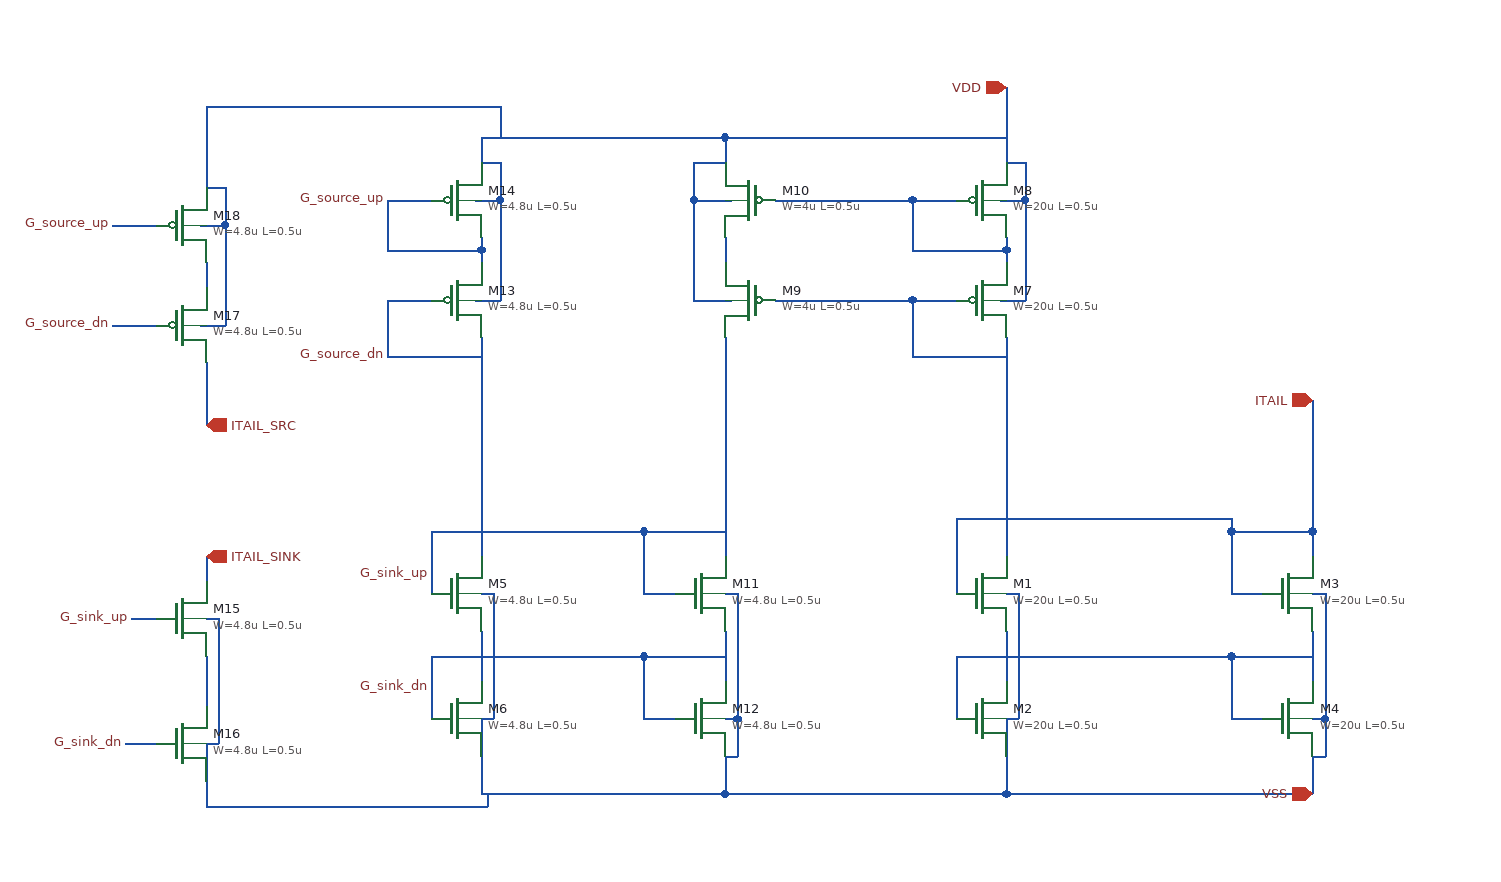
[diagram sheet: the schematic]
v {xschem version=3.4.3 file_version=1.2
}
G {}
K {}
V {}
S {}
E {}
N 575 -225 585 -225 {
lab=VSS}
N 585 -225 585 -125 {
lab=VSS}
N 575 -125 585 -125 {
lab=VSS}
N 575 -190 575 -160 {
lab=#net1}
N 575 -195 575 -190 {
lab=#net1}
N 575 -160 575 -155 {
lab=#net1}
N 575 -125 575 -70 {
lab=VSS}
N 575 -265 575 -255 {
lab=#net2}
N 575 -70 575 -65 {
lab=VSS}
N 575 -430 575 -265 {
lab=#net2}
N 500 -540 535 -540 {
lab=#net3}
N 500 -540 500 -500 {
lab=#net3}
N 500 -500 575 -500 {
lab=#net3}
N 575 -510 575 -500 {
lab=#net3}
N 575 -500 575 -490 {
lab=#net3}
N 570 -460 590 -460 {
lab=VDD}
N 590 -540 590 -460 {
lab=VDD}
N 570 -540 590 -540 {
lab=VDD}
N 590 -570 590 -540 {
lab=VDD}
N 575 -570 590 -570 {
lab=VDD}
N 575 -630 575 -570 {
lab=VDD}
N 500 -460 535 -460 {
lab=#net2}
N 500 -460 500 -415 {
lab=#net2}
N 500 -415 575 -415 {
lab=#net2}
N 390 -540 500 -540 {
lab=#net3}
N 390 -460 500 -460 {
lab=#net2}
N 350 -510 350 -490 {
lab=#net4}
N 350 -590 350 -570 {
lab=VDD}
N 350 -590 575 -590 {
lab=VDD}
N 350 -430 350 -355 {
lab=G_sink_up}
N 325 -460 355 -460 {
lab=VDD}
N 325 -540 325 -460 {
lab=VDD}
N 325 -540 355 -540 {
lab=VDD}
N 325 -540 355 -540 {
lab=VDD}
N 325 -570 325 -540 {
lab=VDD}
N 325 -570 350 -570 {
lab=VDD}
N 350 -355 350 -255 {
lab=G_sink_up}
N 350 -195 350 -155 {
lab=#net5}
N 350 -225 360 -225 {
lab=VSS}
N 360 -225 360 -125 {
lab=VSS}
N 350 -125 360 -125 {
lab=VSS}
N 350 -125 360 -125 {
lab=VSS}
N 360 -125 360 -95 {
lab=VSS}
N 350 -95 360 -95 {
lab=VSS}
N 350 -95 350 -65 {
lab=VSS}
N 350 -65 575 -65 {
lab=VSS}
N 285 -225 310 -225 {
lab=G_sink_up}
N 285 -275 285 -225 {
lab=G_sink_up}
N 285 -175 350 -175 {
lab=#net5}
N 285 -175 285 -125 {
lab=#net5}
N 285 -125 310 -125 {
lab=#net5}
N 285 -275 350 -275 {
lab=G_sink_up}
N 535 -285 535 -225 {
lab=ITAIL}
N 535 -285 755 -285 {
lab=ITAIL}
N 535 -175 535 -125 {
lab=#net6}
N 535 -175 750 -175 {
lab=#net6}
N 820 -195 820 -155 {
lab=#net6}
N 820 -225 830 -225 {
lab=VSS}
N 830 -225 830 -125 {
lab=VSS}
N 820 -125 830 -125 {
lab=VSS}
N 820 -125 830 -125 {
lab=VSS}
N 830 -125 830 -95 {
lab=VSS}
N 820 -95 830 -95 {
lab=VSS}
N 820 -95 820 -65 {
lab=VSS}
N 755 -225 780 -225 {
lab=ITAIL}
N 755 -275 755 -225 {
lab=ITAIL}
N 755 -175 820 -175 {
lab=#net6}
N 755 -175 755 -125 {
lab=#net6}
N 755 -125 780 -125 {
lab=#net6}
N 755 -275 820 -275 {
lab=ITAIL}
N 750 -175 755 -175 {
lab=#net6}
N 755 -285 755 -275 {
lab=ITAIL}
N 820 -275 820 -255 {
lab=ITAIL}
N 575 -65 820 -65 {
lab=VSS}
N 820 -380 820 -275 {
lab=ITAIL}
N 155 -225 165 -225 {
lab=VSS}
N 165 -225 165 -125 {
lab=VSS}
N 155 -125 165 -125 {
lab=VSS}
N 155 -190 155 -160 {
lab=#net7}
N 155 -195 155 -190 {
lab=#net7}
N 155 -160 155 -155 {
lab=#net7}
N 155 -265 155 -255 {
lab=G_source_dn}
N 155 -430 155 -265 {
lab=G_source_dn}
N 80 -540 115 -540 {
lab=G_source_up}
N 80 -540 80 -500 {
lab=G_source_up}
N 80 -500 155 -500 {
lab=G_source_up}
N 155 -510 155 -500 {
lab=G_source_up}
N 155 -500 155 -490 {
lab=G_source_up}
N 150 -460 170 -460 {
lab=VDD}
N 170 -540 170 -460 {
lab=VDD}
N 150 -540 170 -540 {
lab=VDD}
N 170 -570 170 -540 {
lab=VDD}
N 155 -570 170 -570 {
lab=VDD}
N 80 -460 115 -460 {
lab=G_source_dn}
N 80 -460 80 -415 {
lab=G_source_dn}
N 80 -415 155 -415 {
lab=G_source_dn}
N 115 -175 115 -125 {
lab=#net5}
N 155 -95 155 -65 {
lab=VSS}
N 155 -65 350 -65 {
lab=VSS}
N 155 -125 155 -95 {
lab=VSS}
N 155 -590 350 -590 {
lab=VDD}
N 155 -590 155 -570 {
lab=VDD}
N 115 -275 285 -275 {
lab=G_sink_up}
N 115 -275 115 -225 {
lab=G_sink_up}
N 115 -175 285 -175 {
lab=#net5}
N -65 -205 -55 -205 {
lab=VSS}
N -55 -205 -55 -105 {
lab=VSS}
N -65 -105 -55 -105 {
lab=VSS}
N -65 -170 -65 -140 {
lab=#net8}
N -65 -175 -65 -170 {
lab=#net8}
N -65 -140 -65 -135 {
lab=#net8}
N -65 -245 -65 -235 {
lab=ITAIL_SINK}
N -140 -520 -105 -520 {
lab=G_source_up}
N -65 -490 -65 -480 {
lab=#net9}
N -65 -480 -65 -470 {
lab=#net9}
N -70 -440 -50 -440 {
lab=VDD}
N -50 -520 -50 -440 {
lab=VDD}
N -70 -520 -50 -520 {
lab=VDD}
N -50 -550 -50 -520 {
lab=VDD}
N -65 -550 -50 -550 {
lab=VDD}
N -140 -440 -105 -440 {
lab=G_source_dn}
N -65 -105 -65 -75 {
lab=VSS}
N -65 -570 -65 -550 {
lab=VDD}
N -65 -255 -65 -245 {
lab=ITAIL_SINK}
N -130 -105 -105 -105 {
lab=G_sink_dn}
N -65 -615 -65 -570 {
lab=VDD}
N -65 -615 170 -615 {
lab=VDD}
N 170 -615 170 -590 {
lab=VDD}
N -65 -75 -65 -55 {
lab=VSS}
N -65 -55 160 -55 {
lab=VSS}
N 160 -65 160 -55 {
lab=VSS}
N -125 -205 -105 -205 {
lab=G_sink_up}
N -65 -410 -65 -360 {
lab=ITAIL_SRC}
C {symbols/nfet_03v3.sym} 555 -225 0 0 {name=M1
L=0.5u
W=20u
nf=1
m=1
ad="'int((nf+1)/2) * W/nf * 0.18u'"
pd="'2*int((nf+1)/2) * (W/nf + 0.18u)'"
as="'int((nf+2)/2) * W/nf * 0.18u'"
ps="'2*int((nf+2)/2) * (W/nf + 0.18u)'"
nrd="'0.18u / W'" nrs="'0.18u / W'"
sa=0 sb=0 sd=0
model=nfet_03v3
spiceprefix=X
}
C {symbols/nfet_03v3.sym} 555 -125 0 0 {name=M2
L=0.5u
W=20u
nf=1
m=1
ad="'int((nf+1)/2) * W/nf * 0.18u'"
pd="'2*int((nf+1)/2) * (W/nf + 0.18u)'"
as="'int((nf+2)/2) * W/nf * 0.18u'"
ps="'2*int((nf+2)/2) * (W/nf + 0.18u)'"
nrd="'0.18u / W'" nrs="'0.18u / W'"
sa=0 sb=0 sd=0
model=nfet_03v3
spiceprefix=X
}
C {symbols/pfet_03v3.sym} 555 -460 0 0 {name=M7
L=0.5u
W=20u
nf=1
m=1
ad="'int((nf+1)/2) * W/nf * 0.18u'"
pd="'2*int((nf+1)/2) * (W/nf + 0.18u)'"
as="'int((nf+2)/2) * W/nf * 0.18u'"
ps="'2*int((nf+2)/2) * (W/nf + 0.18u)'"
nrd="'0.18u / W'" nrs="'0.18u / W'"
sa=0 sb=0 sd=0
model=pfet_03v3
spiceprefix=X
}
C {symbols/pfet_03v3.sym} 555 -540 0 0 {name=M8
L=0.5u
W=20u
nf=1
m=1
ad="'int((nf+1)/2) * W/nf * 0.18u'"
pd="'2*int((nf+1)/2) * (W/nf + 0.18u)'"
as="'int((nf+2)/2) * W/nf * 0.18u'"
ps="'2*int((nf+2)/2) * (W/nf + 0.18u)'"
nrd="'0.18u / W'" nrs="'0.18u / W'"
sa=0 sb=0 sd=0
model=pfet_03v3
spiceprefix=X
}
C {symbols/pfet_03v3.sym} 370 -460 0 1 {name=M9
L=0.5u
W=4u
nf=1
m=1
ad="'int((nf+1)/2) * W/nf * 0.18u'"
pd="'2*int((nf+1)/2) * (W/nf + 0.18u)'"
as="'int((nf+2)/2) * W/nf * 0.18u'"
ps="'2*int((nf+2)/2) * (W/nf + 0.18u)'"
nrd="'0.18u / W'" nrs="'0.18u / W'"
sa=0 sb=0 sd=0
model=pfet_03v3
spiceprefix=X
}
C {symbols/pfet_03v3.sym} 370 -540 0 1 {name=M10
L=0.5u
W=4u
nf=1
m=1
ad="'int((nf+1)/2) * W/nf * 0.18u'"
pd="'2*int((nf+1)/2) * (W/nf + 0.18u)'"
as="'int((nf+2)/2) * W/nf * 0.18u'"
ps="'2*int((nf+2)/2) * (W/nf + 0.18u)'"
nrd="'0.18u / W'" nrs="'0.18u / W'"
sa=0 sb=0 sd=0
model=pfet_03v3
spiceprefix=X
}
C {symbols/nfet_03v3.sym} 330 -225 0 0 {name=M11
L=0.5u
W=4.8u
nf=1
m=1
ad="'int((nf+1)/2) * W/nf * 0.18u'"
pd="'2*int((nf+1)/2) * (W/nf + 0.18u)'"
as="'int((nf+2)/2) * W/nf * 0.18u'"
ps="'2*int((nf+2)/2) * (W/nf + 0.18u)'"
nrd="'0.18u / W'" nrs="'0.18u / W'"
sa=0 sb=0 sd=0
model=nfet_03v3
spiceprefix=X
}
C {symbols/nfet_03v3.sym} 330 -125 0 0 {name=M12
L=0.5u
W=4.8u
nf=1
m=1
ad="'int((nf+1)/2) * W/nf * 0.18u'"
pd="'2*int((nf+1)/2) * (W/nf + 0.18u)'"
as="'int((nf+2)/2) * W/nf * 0.18u'"
ps="'2*int((nf+2)/2) * (W/nf + 0.18u)'"
nrd="'0.18u / W'" nrs="'0.18u / W'"
sa=0 sb=0 sd=0
model=nfet_03v3
spiceprefix=X
}
C {devices/ipin.sym} 820 -380 0 0 {name=p8 lab=ITAIL}
C {devices/iopin.sym} 575 -630 0 0 {name=p9 lab=VDD}
C {devices/iopin.sym} 820 -65 0 0 {name=p10 lab=VSS}
C {symbols/nfet_03v3.sym} 800 -225 0 0 {name=M3
L=0.5u
W=20u
nf=1
m=1
ad="'int((nf+1)/2) * W/nf * 0.18u'"
pd="'2*int((nf+1)/2) * (W/nf + 0.18u)'"
as="'int((nf+2)/2) * W/nf * 0.18u'"
ps="'2*int((nf+2)/2) * (W/nf + 0.18u)'"
nrd="'0.18u / W'" nrs="'0.18u / W'"
sa=0 sb=0 sd=0
model=nfet_03v3
spiceprefix=X
}
C {symbols/nfet_03v3.sym} 800 -125 0 0 {name=M4
L=0.5u
W=20u
nf=1
m=1
ad="'int((nf+1)/2) * W/nf * 0.18u'"
pd="'2*int((nf+1)/2) * (W/nf + 0.18u)'"
as="'int((nf+2)/2) * W/nf * 0.18u'"
ps="'2*int((nf+2)/2) * (W/nf + 0.18u)'"
nrd="'0.18u / W'" nrs="'0.18u / W'"
sa=0 sb=0 sd=0
model=nfet_03v3
spiceprefix=X
}
C {symbols/nfet_03v3.sym} 135 -225 0 0 {name=M5
L=0.5u
W=4.8u
nf=1
m=1
ad="'int((nf+1)/2) * W/nf * 0.18u'"
pd="'2*int((nf+1)/2) * (W/nf + 0.18u)'"
as="'int((nf+2)/2) * W/nf * 0.18u'"
ps="'2*int((nf+2)/2) * (W/nf + 0.18u)'"
nrd="'0.18u / W'" nrs="'0.18u / W'"
sa=0 sb=0 sd=0
model=nfet_03v3
spiceprefix=X
}
C {symbols/nfet_03v3.sym} 135 -125 0 0 {name=M6
L=0.5u
W=4.8u
nf=1
m=1
ad="'int((nf+1)/2) * W/nf * 0.18u'"
pd="'2*int((nf+1)/2) * (W/nf + 0.18u)'"
as="'int((nf+2)/2) * W/nf * 0.18u'"
ps="'2*int((nf+2)/2) * (W/nf + 0.18u)'"
nrd="'0.18u / W'" nrs="'0.18u / W'"
sa=0 sb=0 sd=0
model=nfet_03v3
spiceprefix=X
}
C {symbols/pfet_03v3.sym} 135 -460 0 0 {name=M13
L=0.5u
W=4.8u
nf=1
m=1
ad="'int((nf+1)/2) * W/nf * 0.18u'"
pd="'2*int((nf+1)/2) * (W/nf + 0.18u)'"
as="'int((nf+2)/2) * W/nf * 0.18u'"
ps="'2*int((nf+2)/2) * (W/nf + 0.18u)'"
nrd="'0.18u / W'" nrs="'0.18u / W'"
sa=0 sb=0 sd=0
model=pfet_03v3
spiceprefix=X
}
C {symbols/pfet_03v3.sym} 135 -540 0 0 {name=M14
L=0.5u
W=4.8u
nf=1
m=1
ad="'int((nf+1)/2) * W/nf * 0.18u'"
pd="'2*int((nf+1)/2) * (W/nf + 0.18u)'"
as="'int((nf+2)/2) * W/nf * 0.18u'"
ps="'2*int((nf+2)/2) * (W/nf + 0.18u)'"
nrd="'0.18u / W'" nrs="'0.18u / W'"
sa=0 sb=0 sd=0
model=pfet_03v3
spiceprefix=X
}
C {symbols/nfet_03v3.sym} -85 -205 0 0 {name=M15
L=0.5u
W=4.8u
nf=1
m=1
ad="'int((nf+1)/2) * W/nf * 0.18u'"
pd="'2*int((nf+1)/2) * (W/nf + 0.18u)'"
as="'int((nf+2)/2) * W/nf * 0.18u'"
ps="'2*int((nf+2)/2) * (W/nf + 0.18u)'"
nrd="'0.18u / W'" nrs="'0.18u / W'"
sa=0 sb=0 sd=0
model=nfet_03v3
spiceprefix=X
}
C {symbols/nfet_03v3.sym} -85 -105 0 0 {name=M16
L=0.5u
W=4.8u
nf=1
m=1
ad="'int((nf+1)/2) * W/nf * 0.18u'"
pd="'2*int((nf+1)/2) * (W/nf + 0.18u)'"
as="'int((nf+2)/2) * W/nf * 0.18u'"
ps="'2*int((nf+2)/2) * (W/nf + 0.18u)'"
nrd="'0.18u / W'" nrs="'0.18u / W'"
sa=0 sb=0 sd=0
model=nfet_03v3
spiceprefix=X
}
C {symbols/pfet_03v3.sym} -85 -440 0 0 {name=M17
L=0.5u
W=4.8u
nf=1
m=1
ad="'int((nf+1)/2) * W/nf * 0.18u'"
pd="'2*int((nf+1)/2) * (W/nf + 0.18u)'"
as="'int((nf+2)/2) * W/nf * 0.18u'"
ps="'2*int((nf+2)/2) * (W/nf + 0.18u)'"
nrd="'0.18u / W'" nrs="'0.18u / W'"
sa=0 sb=0 sd=0
model=pfet_03v3
spiceprefix=X
}
C {symbols/pfet_03v3.sym} -85 -520 0 0 {name=M18
L=0.5u
W=4.8u
nf=1
m=1
ad="'int((nf+1)/2) * W/nf * 0.18u'"
pd="'2*int((nf+1)/2) * (W/nf + 0.18u)'"
as="'int((nf+2)/2) * W/nf * 0.18u'"
ps="'2*int((nf+2)/2) * (W/nf + 0.18u)'"
nrd="'0.18u / W'" nrs="'0.18u / W'"
sa=0 sb=0 sd=0
model=pfet_03v3
spiceprefix=X
}
C {devices/lab_pin.sym} -140 -520 0 0 {name=p1 sig_type=std_logic lab=G_source_up}
C {devices/lab_pin.sym} -140 -440 0 0 {name=p2 sig_type=std_logic lab=G_source_dn}
C {devices/lab_pin.sym} -125 -205 0 0 {name=p6 sig_type=std_logic lab=G_sink_up}
C {devices/lab_pin.sym} -130 -105 0 0 {name=p7 sig_type=std_logic lab=G_sink_dn}
C {devices/opin.sym} -65 -360 0 0 {name=p11 lab=ITAIL_SRC}
C {devices/opin.sym} -65 -255 0 0 {name=p12 lab=ITAIL_SINK}
C {devices/lab_pin.sym} 80 -540 0 0 {name=p3 sig_type=std_logic lab=G_source_up}
C {devices/lab_pin.sym} 80 -415 0 0 {name=p4 sig_type=std_logic lab=G_source_dn}
C {devices/lab_pin.sym} 115 -240 0 0 {name=p5 sig_type=std_logic lab=G_sink_up}
C {devices/lab_pin.sym} 115 -150 0 0 {name=p13 sig_type=std_logic lab=G_sink_dn}
